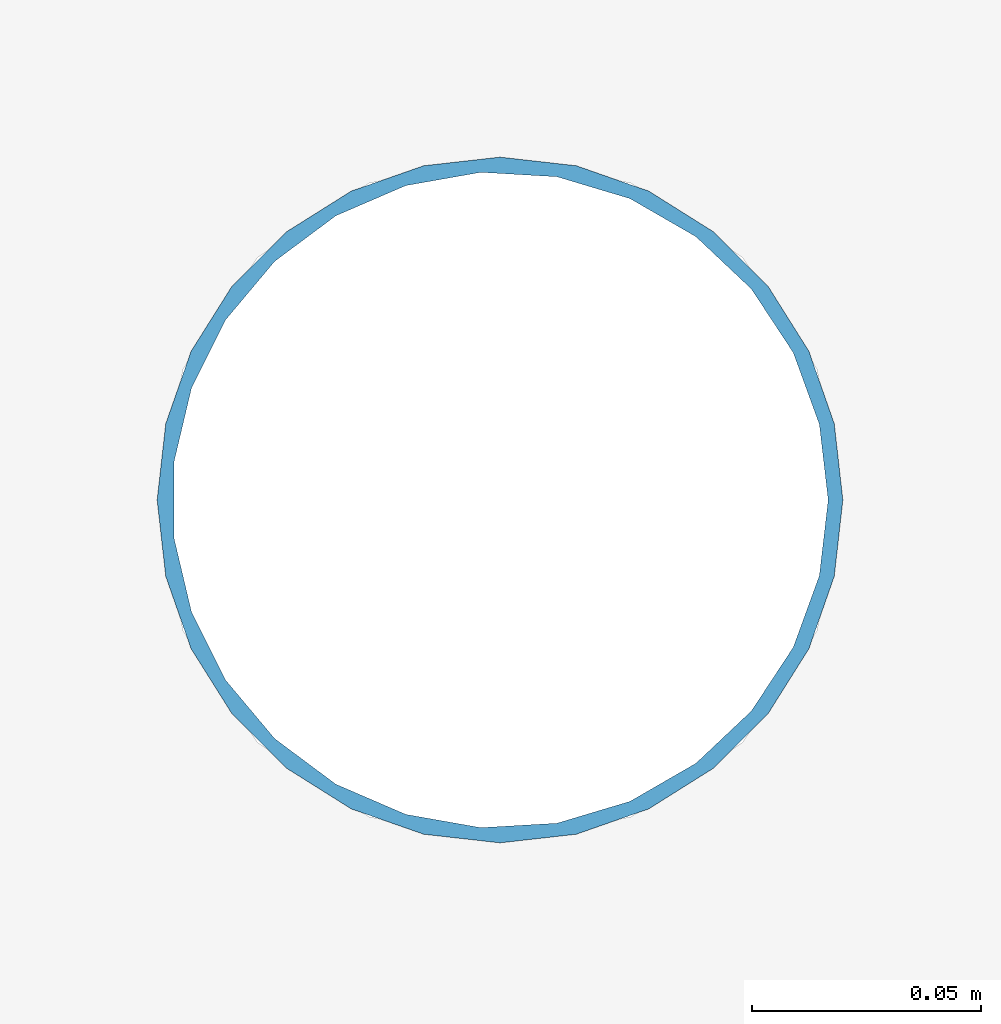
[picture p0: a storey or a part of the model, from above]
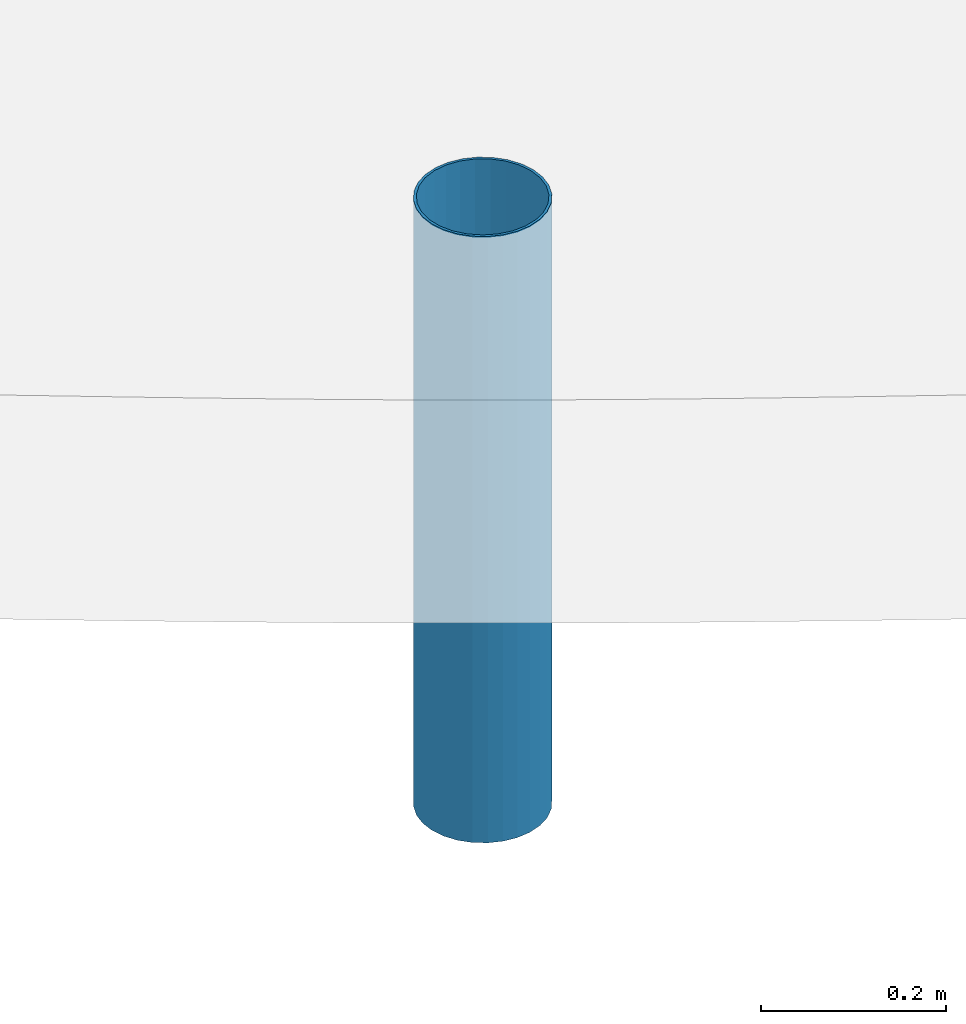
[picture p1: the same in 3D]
Properties of the parts of a building model (IFC2X3)

# File
Description: ViewDefinition [CoordinationView_V2.0], RevitIdentifiers [VersionGUID: 74f4be3d-8174-46b9-96e8-d78cdac258c1, NumberOfSaves: 13], CoordinateReference [CoordinateBase: Shared Coordinates]
Time: 2026-05-06T11:11:03+01:00
Written by: ODA SDAI 22.12
Made in: 23.1.20.70 - Exporter 23.2.5.0 - Alternate UI 23.2.5.0

# IfcProject
Description: ifcDescription; LongName: Buffertank Vaset Renseanlegg; Phase: Skisseprosjekt

# IfcSite, IFCSITE
LongName: SiteLongName; RefLatitude: 59, 54, 44, 239196; RefLongitude: 10, 45, 0, 0; RefElevation: 0 mm; LandTitleNumber: Gårds og Bruksnummer
Pset_ProductRequirements - Category: Project Information

# IfcBuilding
Description: BuildingDescription; LongName: BuildingLongName
Pset_BuildingCommon - BuildingID: BuildingID; NumberOfStoreys: 3
Pset_ProductRequirements - Category: Project Information

# IfcBuildingStorey: Level:8mm Nivåhode Lokale Koter (3)
Pset_ProductRequirements - Category: Levels
Name | LongName = Pset_AirSideSystemInformation, Name = Pset_ProductRequirements, Name | Elevation (mm)
Plan 01 | Plan 01 | 0
Plan 1 pumpehus | Plan 1 pumpehus | 4200
Plan 02 | Plan 02 | 6000

# IfcBuildingElementProxy: Fascia:Vindski - 1 bord 235mm, Fascia:Vindski - 1 bord 235mm:592211
In: Plan 02
Type - Pset_ProductRequirements - Category: Roofs: Fascias
Pset_BuildingElementProxyCommon - Reference: Vindski - 1 bord 235mm; sets with these values: 2
Pset_ProvisionForVoid - Shape: Undefined; Width: 6122 mm; Height: 19 mm; Depth: 19 mm

# IfcBuildingElementProxy: Fascia:Vindski - 2 bord, Fascia:Vindski - 2 bord:592089
In: Plan 02
Type - Pset_ProductRequirements - Category: Roofs: Fascias
Pset_BuildingElementProxyCommon - Reference: Vindski - 2 bord; sets with these values: 2

# IfcBuildingElementProxy: Karmlist Dør:Karmlist Dør, Karmlist Dør:Karmlist Dør:614962
In: Plan 1 pumpehus
Type - Material: Hvit
Type - Pset_ProductRequirements - Category: Generic Models
Pset_BuildingElementProxyCommon - Reference: Karmlist Dør; sets with these values: 2
Pset_ProvisionForVoid - Width: 910 mm; Height: 2110 mm; Depth: 227 mm

# IfcBuildingElementProxy: NV Project Base Point:ARCHITECTURE_ORIGIN, NV Project Base Point:ARCHITECTURE_ORIGIN:390717
In: Plan 01
Type - Material: Grå, <Unnamed>
Type - Pset_ProductRequirements - Category: Generic Models
Pset_BuildingElementProxyCommon - Reference: ARCHITECTURE_ORIGIN; sets with these values: 2
Pset_ProvisionForVoid - Width: 6.27852 mm; Height: 6.27852 mm; Depth: 6.27852 mm

# IfcBuildingElementProxy: Vindusomramming - Kun Vannbrett:Vindusomramming - Kun Vannbrett, Vindusomramming - Kun Vannbrett:Vindusomramming - Kun Vannbrett:614963
In: Plan 1 pumpehus
Type - Material: Hvit(1)
Type - Pset_ProductRequirements - Category: Generic Models
Pset_BuildingElementProxyCommon - Reference: Vindusomramming - Kun Vannbrett; sets with these values: 2
Pset_ProvisionForVoid - Width: 22 mm; Height: 148 mm; Depth: 148 mm

# IfcColumn: Søyle Sirkulær:KR 101.6x3.2, Søyle Sirkulær:KR 101.6x3.2:593785
In: Plan 01
Type - PredefinedType: COLUMN; Material: Stål - S355
Type - Pset_ColumnCommon - IsExternal: no; LoadBearing: yes
Type - Pset_ProductRequirements - Category: Structural Columns
Pset_ColumnCommon - Reference: KR 101.6x3.2
Pset_QuantityTakeOff - Reference: KR 101.6x3.2; sets with these values: 2

# IfcDoor: Enfløyet m omramming:Ytterdør 9x21, Enfløyet m omramming:Ytterdør 9x21:614959
In: Plan 1 pumpehus
Type - OperationType: SINGLE_SWING_LEFT; ConstructionType: USERDEFINED; ParameterTakesPrecedence: no; Sizeable: no; Material: Rustfritt Stål, Hvit(1), Tre
Type - Enfløyet m omramming:Ytterdør 9x21:614959:1 - PanelOperation: SWINGING
Type - Pset_ConcreteElementGeneral - FireRating: -; ConstructionType: TD Tredør
Type - Pset_DoorCommon - IsExternal: yes; FireRating: -
Type - Pset_ProductRequirements - Category: Doors
OverallHeight: 2110 mm; OverallWidth: 910 mm
Pset_DoorCommon - Reference: Ytterdør 9x21
Pset_QuantityTakeOff - Reference: Ytterdør 9x21

# IfcOpeningElement: Opening (5)
Name | In | Reference | sets with these values | Category
Floor:Standard 200mm:416196 | Plan 01 | Standard 200mm | 2 | Lines: <Sketch>
2 x Basic Wall:Yttervegg - 250mm + 100mm Betong med puss 2:568346 | Plan 01 | Ytterdør 9x21 | 2 | Doors
Floor:Standard 200mm:416196 | Plan 1 pumpehus | Standard 200mm | 2 | Lines: <Sketch>
Enfløyet m omramming:Ytterdør 9x21:614959:1 | Plan 1 pumpehus

# IfcRailing: Railing:900mm Stål Ø30 cc120, Railing:900mm Stål Ø30 cc120:615558
In: Plan 1 pumpehus
Material: <Unnamed>, Tre
Pset_ProductRequirements - Category: Railings
Pset_QuantityTakeOff - Reference: 900mm Stål Ø30 cc120
Pset_RailingCommon - IsExternal: no; Reference: 900mm Stål Ø30 cc120; Height: 1219.2 mm

# IfcRoof: Basic Roof:Betong Isolert - 333mm (2)
In: Plan 02
Material: Isolasjon Hard 80 mm, Tak - Plasstøpt betong 260 mm
Pset_ProductRequirements - Category: Roofs
Pset_QuantityTakeOff - Reference: Betong Isolert - 333mm
Pset_RoofCommon - IsExternal: yes; Reference: Betong Isolert - 333mm
Name (Basic Roof:Betong Isolert - 333mm:...) | ProjectedArea (m2) | TotalArea (m2)
564958 | 388.478 | 388.709
567089 | 18.0973 | 18.1066

# IfcRoof: Basic Roof:Standard - papp (2)
In: Plan 02
Material: Asfaltplate 10 mm
Pset_ProductRequirements - Category: Roofs
Pset_QuantityTakeOff - Reference: Standard - papp
Pset_RoofCommon - IsExternal: yes; Reference: Standard - papp
Name (Basic Roof:Standard - papp:...) | ProjectedArea (m2) | TotalArea (m2)
566143 | 393.173 | 393.407
567040 | 18.0973 | 18.1066

# IfcRoof: Basic Roof:Tak Tre 48x198+48 Isolert Eternitt, Basic Roof:Tak Tre 48x198+48 Isolert Eternitt:569476
In: Plan 1 pumpehus
Material: Tak - Eternitt 62 mm, Tre - Lekter 48 mm, Tre - Lekter 198 mm, Tak - Plan Gips 13 mm
Pset_ProductRequirements - Category: Roofs
Pset_QuantityTakeOff - Reference: Tak Tre 48x198+48 Isolert Eternitt
Pset_RoofCommon - IsExternal: yes; Reference: Tak Tre 48x198+48 Isolert Eternitt; ProjectedArea: 37.4789 m2; TotalArea: 39.8842 m2

# IfcSlab: Floor:Standard 200mm (3)
Type - PredefinedType: FLOOR; Material: Betong - Plasstøpt 200 mm
Type - Pset_ElementShading - Roughness: 304.8 mm
Type - Pset_ProductRequirements - Category: Floors
Type - Pset_SlabCommon - IsExternal: no
Pset_QuantityTakeOff - Reference: Standard 200mm; sets with these values: 2
Pset_SlabCommon - Reference: Standard 200mm; LoadBearing: no
Name (Floor:Standard 200mm:...) | In | PitchAngle (deg)
563626 | Plan 01 | 0.98776 | Material: Betong - Plasstøpt
568604 | Plan 01 | 0
569006 | Plan 1 pumpehus | 0

# IfcSlab: SurveyMarker:Custom, SurveyMarker:Custom:390718
In: Plan 01
Type - PredefinedType: BASESLAB; Material: Survey Marker
Type - Pset_ProductRequirements - Category: Structural Foundations
Type - Pset_SlabCommon - IsExternal: no
Pset_QuantityTakeOff - Reference: Custom; sets with these values: 2
Pset_SlabCommon - Reference: Custom

# IfcWallStandardCase: Basic Wall:Innervegg - 250mm (2)
In: Plan 01
Type - PredefinedType: STANDARD; Material: Vegg - Plasstøpt betong 250 mm
Type - Pset_ElementShading - Roughness: 304.8 mm
Type - Pset_ProductRequirements - Category: Walls
Type - Pset_WallCommon - IsExternal: no
Pset_QuantityTakeOff - Reference: Innervegg - 250mm; sets with these values: 2
Pset_WallCommon - LoadBearing: no; ExtendToStructure: no; Reference: Innervegg - 250mm
Name (Basic Wall:Innervegg - 250mm:...)
569219
569450

# IfcWallStandardCase: Basic Wall:Standard Yttervegg 4 sjikt - 400mm (2)
In: Plan 01
Type - PredefinedType: STANDARD; Material: Betong - Plasstøpt 300 mm, Betong - Plasstøpt 120 mm, Isolasjon Hard 100 mm, Betong - Plasstøpt 80 mm
Type - Pset_ElementShading - Roughness: 304.8 mm
Type - Pset_ProductRequirements - Category: Walls
Type - Pset_WallCommon - IsExternal: yes
Pset_QuantityTakeOff - Reference: Standard Yttervegg 4 sjikt - 400mm; sets with these values: 2
Pset_WallCommon - LoadBearing: no; Reference: Standard Yttervegg 4 sjikt - 400mm; ExtendToStructure: no
Name (Basic Wall:Standard Yttervegg 4 sjikt - 400mm:...)
564419
564420

# IfcWallStandardCase: Basic Wall:Standard Yttervegg påforing og panel (2)
In: Plan 01
Type - PredefinedType: STANDARD; Material: Utlekting 48 mm, Dobbelfals Stående Kledning - Hvit 19 mm
Type - Pset_ElementShading - Roughness: 304.8 mm
Type - Pset_ProductRequirements - Category: Walls
Type - Pset_WallCommon - IsExternal: yes
Pset_QuantityTakeOff - Reference: Standard Yttervegg påforing og panel; sets with these values: 2
Pset_WallCommon - LoadBearing: no; ExtendToStructure: no; Reference: Standard Yttervegg påforing og panel
Name (Basic Wall:Standard Yttervegg påforing og panel:...)
566055
566056

# IfcWallStandardCase: Basic Wall:Yttervegg - 250mm + 100mm Betong med puss 2 (4)
In: Plan 01
Type - PredefinedType: STANDARD; Material: Vegg - Puss 10 mm, Isolasjon Hard 100 mm, Betong - Plasstøpt 250 mm
Type - Pset_ElementShading - Roughness: 304.8 mm
Type - Pset_ProductRequirements - Category: Walls
Type - Pset_WallCommon - IsExternal: yes
Pset_QuantityTakeOff - Reference: Yttervegg - 250mm + 100mm Betong med puss 2; sets with these values: 2
Pset_WallCommon - LoadBearing: no; ExtendToStructure: no; Reference: Yttervegg - 250mm + 100mm Betong med puss 2
Name (Basic Wall:Yttervegg - 250mm + 100mm Betong med puss 2:...)
568141
568213
568281
568346

# IfcWallStandardCase: Basic Wall:Yttervegg - VSK 200mm Stender med stående kledning (4)
In: Plan 1 pumpehus
Type - PredefinedType: STANDARD; Material: Dobbelfals Stående Kledning - Hvit 19 mm, Vegg 19 mm, Luftsjikt 11 mm, Asfaltplate 12 mm, Stender/Isolasjon 198 mm, Vegg 48 mm, Vegg - Gips 13 mm
Type - Pset_ElementShading - Roughness: 304.8 mm
Type - Pset_ProductRequirements - Category: Walls
Type - Pset_WallCommon - IsExternal: yes
Pset_QuantityTakeOff - Reference: Yttervegg - VSK 200mm Stender med stående kledning; sets with these values: 2
Pset_WallCommon - LoadBearing: no; Reference: Yttervegg - VSK 200mm Stender med stående kledning; ExtendToStructure: yes
Name (Basic Wall:Yttervegg - VSK 200mm Stender med stående kledning:...)
590836
590999
591098
591234
